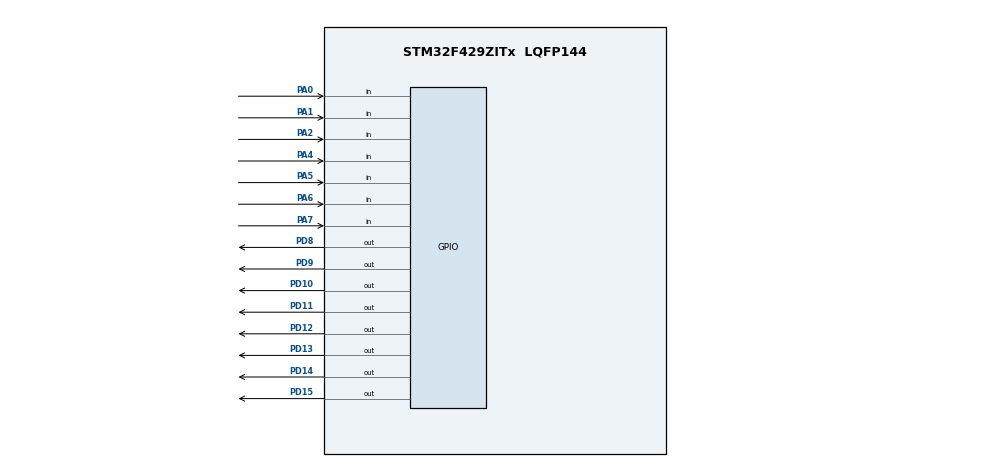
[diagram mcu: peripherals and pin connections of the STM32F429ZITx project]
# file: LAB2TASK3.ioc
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Mcu.Family=STM32F4
Mcu.Name=STM32F429ZITx
Mcu.Package=LQFP144
NVIC.PriorityGroup=NVIC_PRIORITYGROUP_4
PA0/WKUP.Signal=GPIO_Input
PA1.Signal=GPIO_Input
PA2.Signal=GPIO_Input
PA4.Signal=GPIO_Input
PA5.Signal=GPIO_Input
PA6.Signal=GPIO_Input
PA7.Signal=GPIO_Input
PD10.Signal=GPIO_Output
PD11.Signal=GPIO_Output
PD12.Signal=GPIO_Output
PD13.Signal=GPIO_Output
PD14.Signal=GPIO_Output
PD15.Signal=GPIO_Output
PD8.Signal=GPIO_Output
PD9.Signal=GPIO_Output
PH0/OSC_IN.Mode=HSE-External-Oscillator
PH0/OSC_IN.Signal=RCC_OSC_IN
PH1/OSC_OUT.Mode=HSE-External-Oscillator
PH1/OSC_OUT.Signal=RCC_OSC_OUT
ProjectManager.HeapSize=0x200
ProjectManager.StackSize=0x400
ProjectManager.TargetToolchain=EWARM V8.32
RCC.48MHZClocksFreq_Value=64000000
RCC.AHBFreq_Value=128000000
RCC.APB1CLKDivider=RCC_HCLK_DIV4
RCC.APB1Freq_Value=32000000
RCC.APB1TimFreq_Value=64000000
RCC.APB2CLKDivider=RCC_HCLK_DIV2
RCC.APB2Freq_Value=64000000
RCC.APB2TimFreq_Value=128000000
RCC.CortexFreq_Value=128000000
RCC.HCLKFreq_Value=128000000
RCC.HSE_VALUE=8000000
RCC.HSI_VALUE=16000000
RCC.LSE_VALUE=32768
RCC.PLLM=4
RCC.PLLN=128
RCC.PLLSourceVirtual=RCC_PLLSOURCE_HSE
RCC.SYSCLKFreq_VALUE=128000000
RCC.SYSCLKSource=RCC_SYSCLKSOURCE_PLLCLK
RCC.VCOOutputFreq_Value=256000000
board=custom

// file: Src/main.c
/* USER CODE BEGIN Header */

/**

  ******************************************************************************

  * @file           : main.c

  * @brief          : Main program body

  ******************************************************************************

  * @attention

  *

  * <h2><center>&copy; Copyright (c) 2020 STMicroelectronics.

  * All rights reserved.</center></h2>

  *

  * This software component is licensed by ST under BSD 3-Clause license,

  * the "License"; You may not use this file except in compliance with the

  * License. You may obtain a copy of the License at:

  *                        opensource.org/licenses/BSD-3-Clause

  *

  ******************************************************************************

  */

/* USER CODE END Header */

#include "main.h"

void SystemClock_Config(void);

static void MX_GPIO_Init(void);

int main(void)

{

  /* USER CODE BEGIN 1 */

  uint16_t input = 0x0000;

  uint16_t nibble1 = 0x0000;

  uint16_t nibble2 = 0x0000;

  uint16_t result = 0x0000;

  /* USER CODE END 1 */

  /* MCU Configuration--------------------------------------------------------*/

  /* Reset of all peripherals, Initializes the Flash interface and the Systick. */

  HAL_Init();

  /* Configure the system clock */

  SystemClock_Config();

  /* Initialize all configured peripherals */

  MX_GPIO_Init();

  /* Infinite loop */

  /* USER CODE BEGIN WHILE */

  while (1)

  {

    //GPIOD -> ODR = 0x3C00;

    //GPIOD -> ODR = 0xC300;

    input = GPIOA -> IDR;

    //input = input << 8;

    //GPIOD -> ODR = input;

    nibble1 = input & 0x000F;

    nibble2 = (input & 0x00F0) >> 4;

    result = nibble1 + nibble2;

    result = result << 8;

    GPIOD -> ODR = result;

    /* USER CODE END WHILE */

  }

}

void SystemClock_Config(void)

{

  RCC_OscInitTypeDef RCC_OscInitStruct = {0};

  RCC_ClkInitTypeDef RCC_ClkInitStruct = {0};

  /** Configure the main internal regulator output voltage

  */

  __HAL_RCC_PWR_CLK_ENABLE();

  __HAL_PWR_VOLTAGESCALING_CONFIG(PWR_REGULATOR_VOLTAGE_SCALE2);

  /** Initializes the CPU, AHB and APB busses clocks

  */

  RCC_OscInitStruct.OscillatorType = RCC_OSCILLATORTYPE_HSE;

  RCC_OscInitStruct.HSEState = RCC_HSE_ON;

  RCC_OscInitStruct.PLL.PLLState = RCC_PLL_ON;

  RCC_OscInitStruct.PLL.PLLSource = RCC_PLLSOURCE_HSE;

  RCC_OscInitStruct.PLL.PLLM = 25;

  RCC_OscInitStruct.PLL.PLLN = 256;

  RCC_OscInitStruct.PLL.PLLP = RCC_PLLP_DIV2;

  RCC_OscInitStruct.PLL.PLLQ = 4;

  if (HAL_RCC_OscConfig(&RCC_OscInitStruct) != HAL_OK)

  {

    Error_Handler();

  }

  /** Initializes the CPU, AHB and APB busses clocks

  */

  RCC_ClkInitStruct.ClockType = RCC_CLOCKTYPE_HCLK|RCC_CLOCKTYPE_SYSCLK

                              |RCC_CLOCKTYPE_PCLK1|RCC_CLOCKTYPE_PCLK2;

  RCC_ClkInitStruct.SYSCLKSource = RCC_SYSCLKSOURCE_PLLCLK;

  RCC_ClkInitStruct.AHBCLKDivider = RCC_SYSCLK_DIV1;

  RCC_ClkInitStruct.APB1CLKDivider = RCC_HCLK_DIV4;

  RCC_ClkInitStruct.APB2CLKDivider = RCC_HCLK_DIV2;

  if (HAL_RCC_ClockConfig(&RCC_ClkInitStruct, FLASH_LATENCY_4) != HAL_OK)

  {

    Error_Handler();

  }

}

static void MX_GPIO_Init(void)

{

  GPIO_InitTypeDef GPIO_InitStruct = {0};

  /* GPIO Ports Clock Enable */

  __HAL_RCC_GPIOH_CLK_ENABLE();

  __HAL_RCC_GPIOA_CLK_ENABLE();

  __HAL_RCC_GPIOD_CLK_ENABLE();

  /*Configure GPIO pin Output Level */

  HAL_GPIO_WritePin(GPIOD, GPIO_PIN_8|GPIO_PIN_9|GPIO_PIN_10|GPIO_PIN_12

                          |GPIO_PIN_13|GPIO_PIN_14|GPIO_PIN_15, GPIO_PIN_RESET);

  /*Configure GPIO pin Output Level */

  HAL_GPIO_WritePin(GPIOD, GPIO_PIN_11, GPIO_PIN_SET);

  /*Configure GPIO pins : PA0 PA1 PA2 PA3

                           PA4 PA5 PA6 PA7 */

  GPIO_InitStruct.Pin = GPIO_PIN_0|GPIO_PIN_1|GPIO_PIN_2|GPIO_PIN_3

                          |GPIO_PIN_4|GPIO_PIN_5|GPIO_PIN_6|GPIO_PIN_7;

  GPIO_InitStruct.Mode = GPIO_MODE_INPUT;

  GPIO_InitStruct.Pull = GPIO_NOPULL;

  HAL_GPIO_Init(GPIOA, &GPIO_InitStruct);

  /*Configure GPIO pins : PD8 PD9 PD10 PD11

                           PD12 PD13 PD14 PD15 */

  GPIO_InitStruct.Pin = GPIO_PIN_8|GPIO_PIN_9|GPIO_PIN_10|GPIO_PIN_11

                          |GPIO_PIN_12|GPIO_PIN_13|GPIO_PIN_14|GPIO_PIN_15;

  GPIO_InitStruct.Mode = GPIO_MODE_OUTPUT_PP;

  GPIO_InitStruct.Pull = GPIO_NOPULL;

  GPIO_InitStruct.Speed = GPIO_SPEED_FREQ_VERY_HIGH;

  HAL_GPIO_Init(GPIOD, &GPIO_InitStruct);

}

void Error_Handler(void)

{

}

/************************ (C) COPYRIGHT STMicroelectronics *****END OF FILE****/
